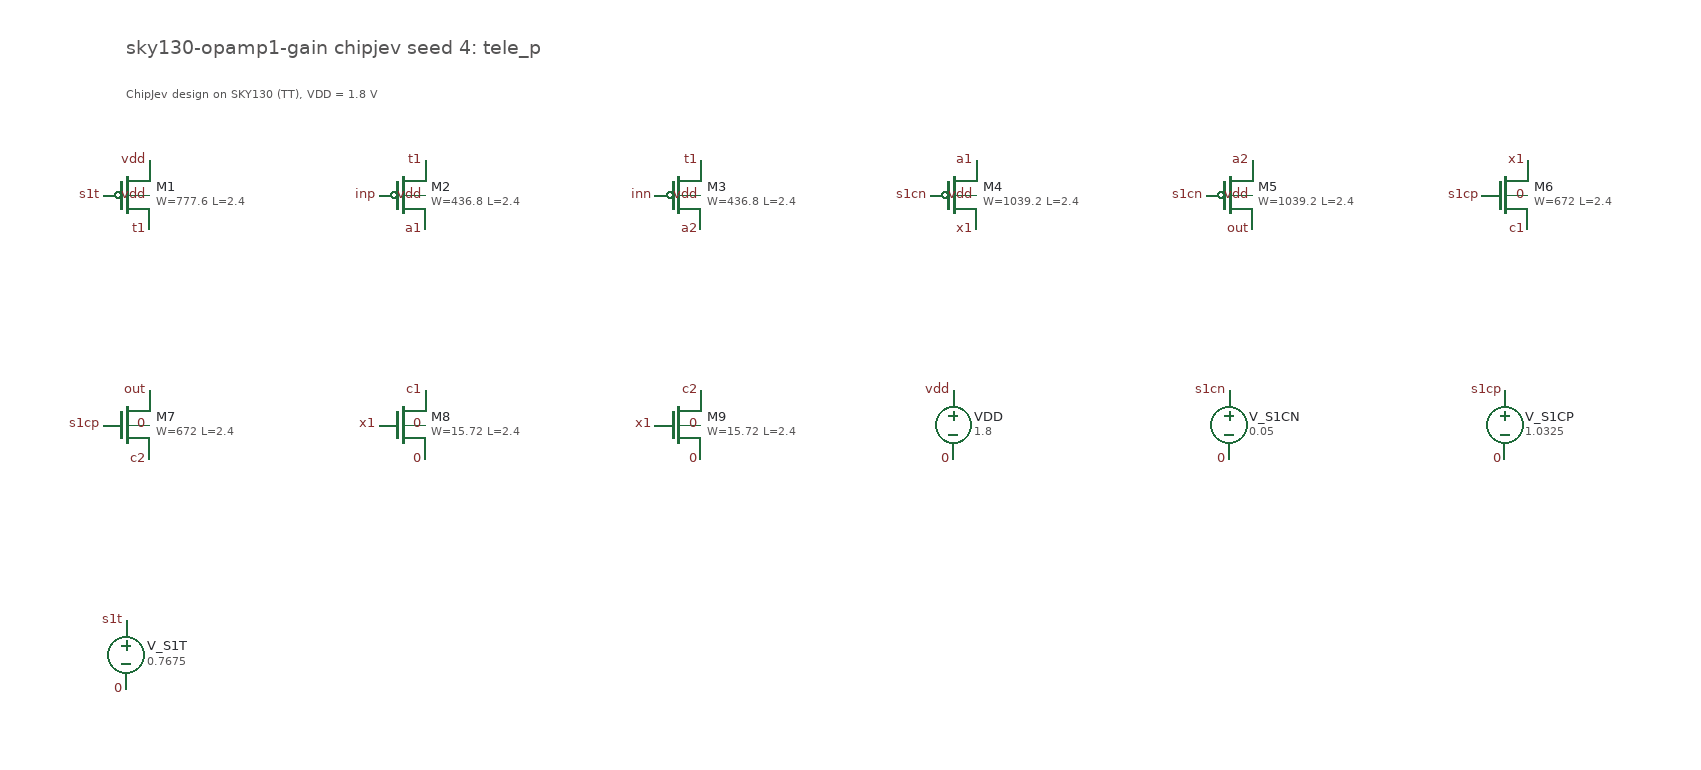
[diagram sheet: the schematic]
v {xschem version=3.4.5 file_version=1.2}
G {}
K {}
V {}
S {}
E {}
T {sky130-opamp1-gain chipjev seed 4: tele_p} 0 -140 0 0 0.5 0.5 {}
T {ChipJev design on SKY130 (TT), VDD = 1.8 V} 0 -100 0 0 0.3 0.3 {}
C {sky130_fd_pr/pfet_01v8.sym} 0 0 0 0 {name=M1 L=2.4 W=777.6 nf=16 mult=1 ad=112.752 as=126.846 pd=782.24 ps=880.02 nrd=0.000372942 nrs=0.000372942 sa=0 sb=0 sd=0 model=pfet_01v8 spiceprefix=X}
C {devices/lab_pin.sym} 20 30 0 0 {name=l1 sig_type=std_logic lab=t1}
C {devices/lab_pin.sym} -20 0 0 0 {name=l2 sig_type=std_logic lab=s1t}
C {devices/lab_pin.sym} 20 -30 0 0 {name=l3 sig_type=std_logic lab=vdd}
C {devices/lab_pin.sym} 20 0 0 0 {name=l4 sig_type=std_logic lab=vdd}
C {sky130_fd_pr/pfet_01v8.sym} 240 0 0 0 {name=M2 L=2.4 W=436.8 nf=9 mult=1 ad=70.3733 as=70.3733 pd=488.233 ps=488.233 nrd=0.000663919 nrs=0.000663919 sa=0 sb=0 sd=0 model=pfet_01v8 spiceprefix=X}
C {devices/lab_pin.sym} 260 30 0 0 {name=l5 sig_type=std_logic lab=a1}
C {devices/lab_pin.sym} 220 0 0 0 {name=l6 sig_type=std_logic lab=inp}
C {devices/lab_pin.sym} 260 -30 0 0 {name=l7 sig_type=std_logic lab=t1}
C {devices/lab_pin.sym} 260 0 0 0 {name=l8 sig_type=std_logic lab=vdd}
C {sky130_fd_pr/pfet_01v8.sym} 480 0 0 0 {name=M3 L=2.4 W=436.8 nf=9 mult=1 ad=70.3733 as=70.3733 pd=488.233 ps=488.233 nrd=0.000663919 nrs=0.000663919 sa=0 sb=0 sd=0 model=pfet_01v8 spiceprefix=X}
C {devices/lab_pin.sym} 500 30 0 0 {name=l9 sig_type=std_logic lab=a2}
C {devices/lab_pin.sym} 460 0 0 0 {name=l10 sig_type=std_logic lab=inn}
C {devices/lab_pin.sym} 500 -30 0 0 {name=l11 sig_type=std_logic lab=t1}
C {devices/lab_pin.sym} 500 0 0 0 {name=l12 sig_type=std_logic lab=vdd}
C {sky130_fd_pr/pfet_01v8.sym} 720 0 0 0 {name=M4 L=2.4 W=1039.2 nf=21 mult=1 ad=157.859 as=157.859 pd=1095.07 ps=1095.07 nrd=0.000279061 nrs=0.000279061 sa=0 sb=0 sd=0 model=pfet_01v8 spiceprefix=X}
C {devices/lab_pin.sym} 740 30 0 0 {name=l13 sig_type=std_logic lab=x1}
C {devices/lab_pin.sym} 700 0 0 0 {name=l14 sig_type=std_logic lab=s1cn}
C {devices/lab_pin.sym} 740 -30 0 0 {name=l15 sig_type=std_logic lab=a1}
C {devices/lab_pin.sym} 740 0 0 0 {name=l16 sig_type=std_logic lab=vdd}
C {sky130_fd_pr/pfet_01v8.sym} 960 0 0 0 {name=M5 L=2.4 W=1039.2 nf=21 mult=1 ad=157.859 as=157.859 pd=1095.07 ps=1095.07 nrd=0.000279061 nrs=0.000279061 sa=0 sb=0 sd=0 model=pfet_01v8 spiceprefix=X}
C {devices/lab_pin.sym} 980 30 0 0 {name=l17 sig_type=std_logic lab=out}
C {devices/lab_pin.sym} 940 0 0 0 {name=l18 sig_type=std_logic lab=s1cn}
C {devices/lab_pin.sym} 980 -30 0 0 {name=l19 sig_type=std_logic lab=a2}
C {devices/lab_pin.sym} 980 0 0 0 {name=l20 sig_type=std_logic lab=vdd}
C {sky130_fd_pr/nfet_01v8.sym} 1200 0 0 0 {name=M6 L=2.4 W=672 nf=14 mult=1 ad=97.44 as=111.36 pd=676.06 ps=772.64 nrd=0.000431548 nrs=0.000431548 sa=0 sb=0 sd=0 model=nfet_01v8 spiceprefix=X}
C {devices/lab_pin.sym} 1220 -30 0 0 {name=l21 sig_type=std_logic lab=x1}
C {devices/lab_pin.sym} 1180 0 0 0 {name=l22 sig_type=std_logic lab=s1cp}
C {devices/lab_pin.sym} 1220 30 0 0 {name=l23 sig_type=std_logic lab=c1}
C {devices/lab_pin.sym} 1220 0 0 0 {name=l24 sig_type=std_logic lab=0}
C {sky130_fd_pr/nfet_01v8.sym} 0 200 0 0 {name=M7 L=2.4 W=672 nf=14 mult=1 ad=97.44 as=111.36 pd=676.06 ps=772.64 nrd=0.000431548 nrs=0.000431548 sa=0 sb=0 sd=0 model=nfet_01v8 spiceprefix=X}
C {devices/lab_pin.sym} 20 170 0 0 {name=l25 sig_type=std_logic lab=out}
C {devices/lab_pin.sym} -20 200 0 0 {name=l26 sig_type=std_logic lab=s1cp}
C {devices/lab_pin.sym} 20 230 0 0 {name=l27 sig_type=std_logic lab=c2}
C {devices/lab_pin.sym} 20 200 0 0 {name=l28 sig_type=std_logic lab=0}
C {sky130_fd_pr/nfet_01v8.sym} 240 200 0 0 {name=M8 L=2.4 W=15.72 nf=1 mult=1 ad=4.5588 as=4.5588 pd=32.02 ps=32.02 nrd=0.0184478 nrs=0.0184478 sa=0 sb=0 sd=0 model=nfet_01v8 spiceprefix=X}
C {devices/lab_pin.sym} 260 170 0 0 {name=l29 sig_type=std_logic lab=c1}
C {devices/lab_pin.sym} 220 200 0 0 {name=l30 sig_type=std_logic lab=x1}
C {devices/lab_pin.sym} 260 230 0 0 {name=l31 sig_type=std_logic lab=0}
C {devices/lab_pin.sym} 260 200 0 0 {name=l32 sig_type=std_logic lab=0}
C {sky130_fd_pr/nfet_01v8.sym} 480 200 0 0 {name=M9 L=2.4 W=15.72 nf=1 mult=1 ad=4.5588 as=4.5588 pd=32.02 ps=32.02 nrd=0.0184478 nrs=0.0184478 sa=0 sb=0 sd=0 model=nfet_01v8 spiceprefix=X}
C {devices/lab_pin.sym} 500 170 0 0 {name=l33 sig_type=std_logic lab=c2}
C {devices/lab_pin.sym} 460 200 0 0 {name=l34 sig_type=std_logic lab=x1}
C {devices/lab_pin.sym} 500 230 0 0 {name=l35 sig_type=std_logic lab=0}
C {devices/lab_pin.sym} 500 200 0 0 {name=l36 sig_type=std_logic lab=0}
C {devices/vsource.sym} 720 200 0 0 {name=VDD value=1.8 m=1}
C {devices/lab_pin.sym} 720 170 0 0 {name=l37 sig_type=std_logic lab=vdd}
C {devices/lab_pin.sym} 720 230 0 0 {name=l38 sig_type=std_logic lab=0}
C {devices/vsource.sym} 960 200 0 0 {name=V_S1CN value=0.05 m=1}
C {devices/lab_pin.sym} 960 170 0 0 {name=l39 sig_type=std_logic lab=s1cn}
C {devices/lab_pin.sym} 960 230 0 0 {name=l40 sig_type=std_logic lab=0}
C {devices/vsource.sym} 1200 200 0 0 {name=V_S1CP value=1.0325 m=1}
C {devices/lab_pin.sym} 1200 170 0 0 {name=l41 sig_type=std_logic lab=s1cp}
C {devices/lab_pin.sym} 1200 230 0 0 {name=l42 sig_type=std_logic lab=0}
C {devices/vsource.sym} 0 400 0 0 {name=V_S1T value=0.7675 m=1}
C {devices/lab_pin.sym} 0 370 0 0 {name=l43 sig_type=std_logic lab=s1t}
C {devices/lab_pin.sym} 0 430 0 0 {name=l44 sig_type=std_logic lab=0}
